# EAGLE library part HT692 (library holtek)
318 Series of Decoders Momentary Series Source: http://www.holtek.com.tw/pdf/consumer/3_18dv110.pdf

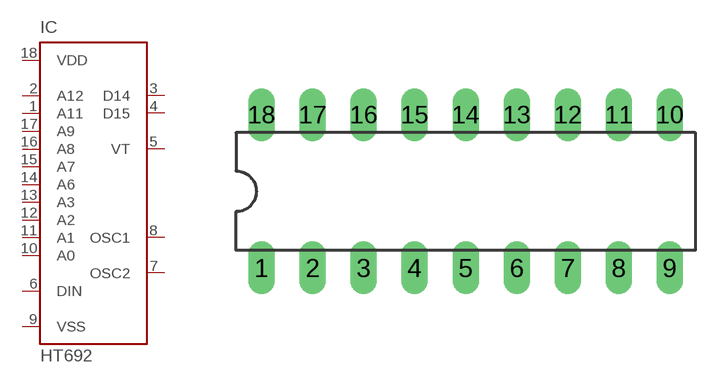
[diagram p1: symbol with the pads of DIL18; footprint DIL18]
Designator prefix IC

## HT692 (OC_FARNELL: unknown; OC_NEWARK: unknown)  [DIL18]
1  A11  in
2  A12  in
3  D14  out
4  D15  out
5  VT  out
6  DIN  in
7  OSC2  out
8  OSC1  in
9  VSS  pwr
10  A0  in
11  A1  in
12  A2  in
13  A3  in
14  A6  in
15  A7  in
16  A8  in
17  A9  in
18  VDD  pwr

## Footprint DIL18 (pad centres in mm)
Dual In Line Package
drill 0.813 long: 1 -10.16,-3.81; 2 -7.62,-3.81; 3 -5.08,-3.81; 4 -2.54,-3.81; 5 0,-3.81; 6 2.54,-3.81; 7 5.08,-3.81; 8 7.62,-3.81; 9 10.16,-3.81; 10 10.16,3.81; 11 7.62,3.81; 12 5.08,3.81; 13 2.54,3.81; 14 0,3.81; 15 -2.54,3.81; 16 -5.08,3.81; 17 -7.62,3.81; 18 -10.16,3.81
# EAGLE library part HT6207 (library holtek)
318 Series of Encoders DATA trigger type Source: http://www.holtek.com.tw/pdf/consumer/3_18ev110.pdf

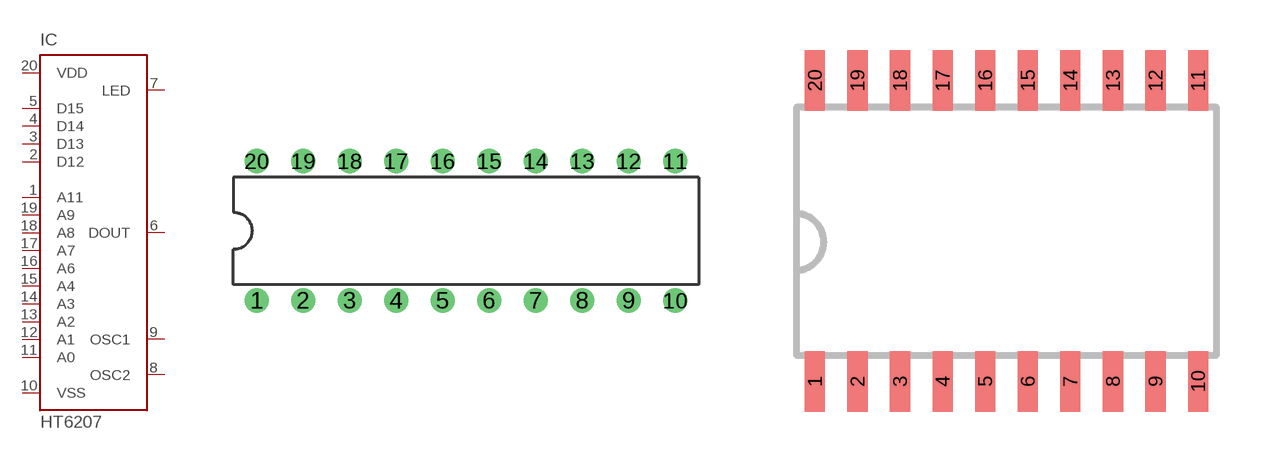
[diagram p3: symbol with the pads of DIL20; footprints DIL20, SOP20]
Designator prefix IC

## HT6207 (OC_FARNELL: unknown; OC_NEWARK: unknown)  [DIL20]
1  A11  in
2  D12  in
3  D13  in
4  D14  in
5  D15  in
6  DOUT  in
7  LED  in
8  OSC2  out
9  OSC1  in
10  VSS  pwr
11  A0  in
12  A1  in
13  A2  in
14  A3  in
15  A4  in
16  A6  in
17  A7  in
18  A8  in
19  A9  in
20  VDD  pwr

## HT6207D (OC_FARNELL: unknown; OC_NEWARK: unknown)  [SOP20]
Pads as for DIL20

## Footprint DIL20 (pad centres in mm)
20-pin Dual In Line Package Source: http://www.holtek.com.tw/pdf/consumer/3_18dv110.pdf
drill 0.813 round: 1 -11.43,-3.81; 2 -8.89,-3.81; 3 -6.35,-3.81; 4 -3.81,-3.81; 5 -1.27,-3.81; 6 1.27,-3.81; 7 3.81,-3.81; 8 6.35,-3.81; 9 8.89,-3.81; 10 11.43,-3.81; 11 11.43,3.81; 12 8.89,3.81; 13 6.35,3.81; 14 3.81,3.81; 15 1.27,3.81; 16 -1.27,3.81; 17 -3.81,3.81; 18 -6.35,3.81; 19 -8.89,3.81; 20 -11.43,3.81

## Footprint SOP20 (pad centres in mm)
20-pin SOP (300mil) Outline Dimensions Source: http://www.holtek.com.tw/pdf/consumer/3_18dv110.pdf
smd 0.6 x 1.8: 1 -5.715,-4.475; 2 -4.445,-4.475; 3 -3.175,-4.475; 4 -1.905,-4.475; 5 -0.635,-4.475; 6 0.635,-4.475; 7 1.905,-4.475; 8 3.175,-4.475; 9 4.445,-4.475; 10 5.715,-4.475; 11 5.715,4.5; 12 4.445,4.5; 13 3.175,4.5; 14 1.905,4.5; 15 0.635,4.5; 16 -0.635,4.5; 17 -1.905,4.5; 18 -3.175,4.5; 19 -4.445,4.5; 20 -5.715,4.5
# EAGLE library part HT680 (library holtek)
318 Series of Encoders TE trigger type Source: http://www.holtek.com.tw/pdf/consumer/3_18ev110.pdf

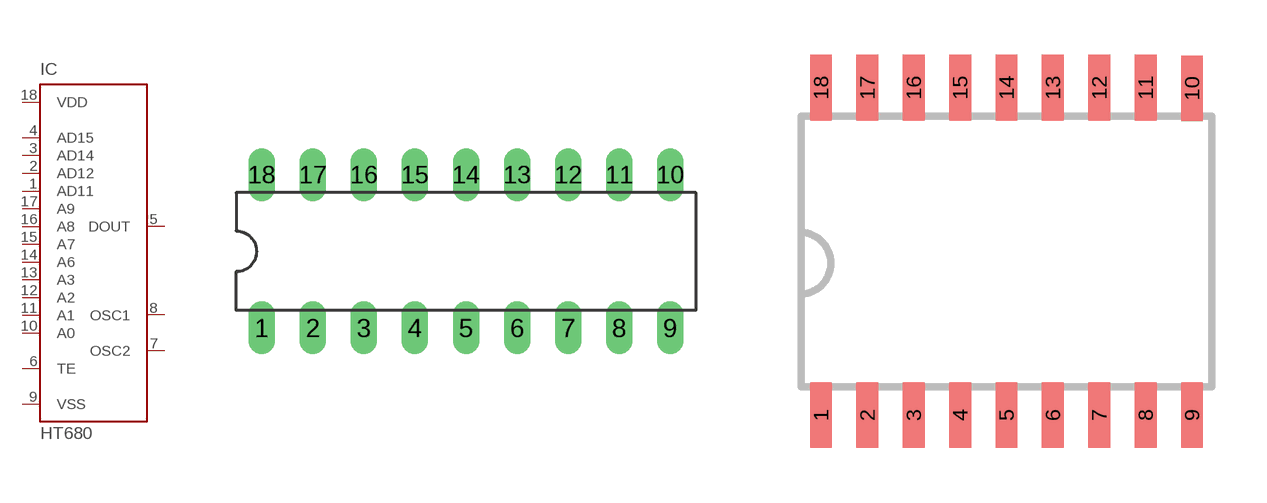
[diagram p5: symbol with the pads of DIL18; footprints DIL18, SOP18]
Designator prefix IC

## HT680 (OC_FARNELL: unknown; OC_NEWARK: unknown)  [DIL18]
1  AD11  in
2  AD12  in
3  AD14  in
4  AD15  in
5  DOUT  in
6  TE  in
7  OSC2  out
8  OSC1  in
9  VSS  pwr
10  A0  in
11  A1  in
12  A2  in
13  A3  in
14  A6  in
15  A7  in
16  A8  in
17  A9  in
18  VDD  pwr

## HT680D (OC_FARNELL: unknown; OC_NEWARK: unknown)  [SOP18]
Pads as for DIL18

## Footprint DIL18 (pad centres in mm)
Dual In Line Package
drill 0.813 long: 1 -10.16,-3.81; 2 -7.62,-3.81; 3 -5.08,-3.81; 4 -2.54,-3.81; 5 0,-3.81; 6 2.54,-3.81; 7 5.08,-3.81; 8 7.62,-3.81; 9 10.16,-3.81; 10 10.16,3.81; 11 7.62,3.81; 12 5.08,3.81; 13 2.54,3.81; 14 0,3.81; 15 -2.54,3.81; 16 -5.08,3.81; 17 -7.62,3.81; 18 -10.16,3.81

## Footprint SOP18 (pad centres in mm)
18-pin SOP (300mil) Outline Dimensions Source: http://www.holtek.com.tw/pdf/consumer/3_18ev110.pdf
smd 0.6 x 1.8: 1 -5.08,-4.475; 2 -3.81,-4.475; 3 -2.54,-4.475; 4 -1.27,-4.475; 5 0,-4.475; 6 1.27,-4.475; 7 2.54,-4.475; 8 3.81,-4.475; 9 5.08,-4.475; 10 5.08,4.475; 11 3.81,4.5; 12 2.54,4.5; 13 1.27,4.5; 14 0,4.5; 15 -1.27,4.5; 16 -2.54,4.5; 17 -3.81,4.5; 18 -5.08,4.5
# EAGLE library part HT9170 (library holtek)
DTMF Receiver Source: http://www.holtek.com/pdf/comm/9170v111.pdf

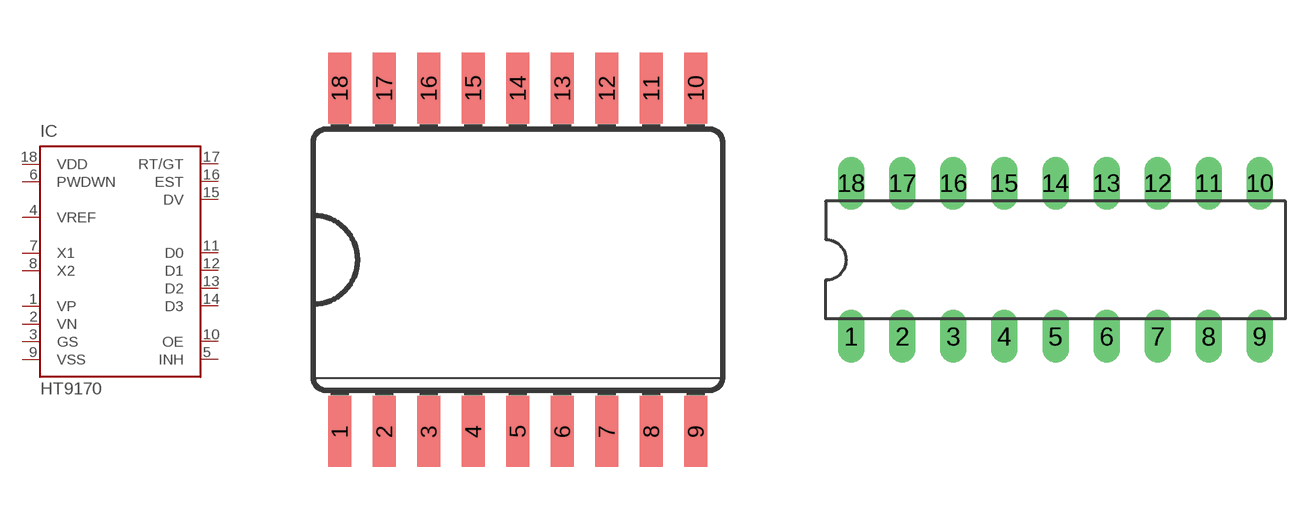
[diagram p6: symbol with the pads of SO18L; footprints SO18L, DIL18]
Designator prefix IC

## HT9170D (MF: HOLTEK; MPN: HT9170D-18SOPLF; OC_FARNELL: 1420879; OC_NEWARK: 53M7847)  [SO18L]
1  VP  in
2  VN  in
3  GS  pas
4  VREF  out
5  INH  in
6  PWDWN  in
7  X1  in
8  X2  out
9  VSS  pwr
10  OE  in
11  D0  out
12  D1  out
13  D2  out
14  D3  out
15  DV  out
16  EST  out
17  RT/GT
18  VDD  pwr

## HT9170B (OC_FARNELL: unknown; OC_NEWARK: unknown)  [DIL18]
Pads as for SO18L

## Footprint SO18L (pad centres in mm)
Small Outline Package 300 mil
smd 0.66 x 2.032: 1 -5.08,-4.902; 2 -3.81,-4.902; 3 -2.54,-4.902; 4 -1.27,-4.902; 5 0,-4.902; 6 1.27,-4.902; 7 2.54,-4.902; 8 3.81,-4.902; 9 5.08,-4.902; 10 5.08,4.902; 11 3.81,4.902; 12 2.54,4.902; 13 1.27,4.902; 14 0,4.902; 15 -1.27,4.902; 16 -2.54,4.902; 17 -3.81,4.902; 18 -5.08,4.902

## Footprint DIL18 (pad centres in mm)
Dual In Line Package
drill 0.813 long: 1 -10.16,-3.81; 2 -7.62,-3.81; 3 -5.08,-3.81; 4 -2.54,-3.81; 5 0,-3.81; 6 2.54,-3.81; 7 5.08,-3.81; 8 7.62,-3.81; 9 10.16,-3.81; 10 10.16,3.81; 11 7.62,3.81; 12 5.08,3.81; 13 2.54,3.81; 14 0,3.81; 15 -2.54,3.81; 16 -5.08,3.81; 17 -7.62,3.81; 18 -10.16,3.81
